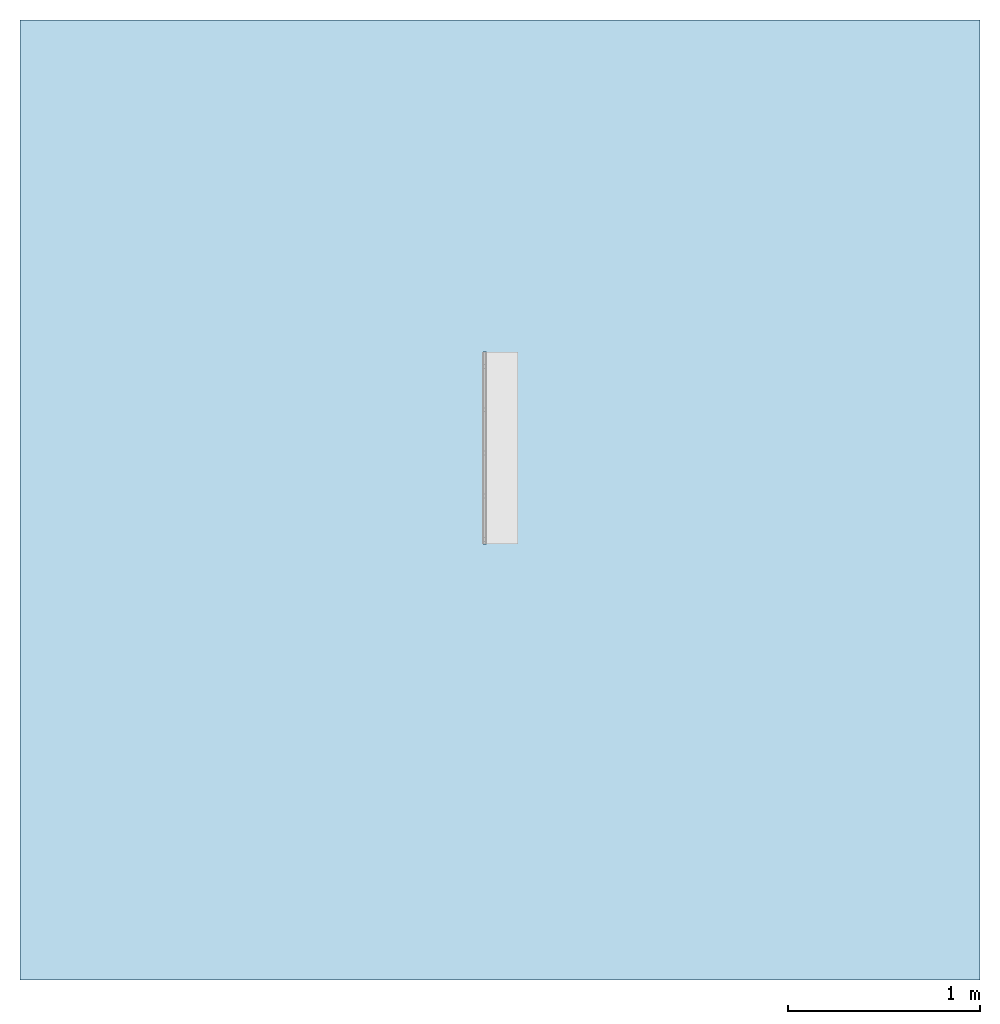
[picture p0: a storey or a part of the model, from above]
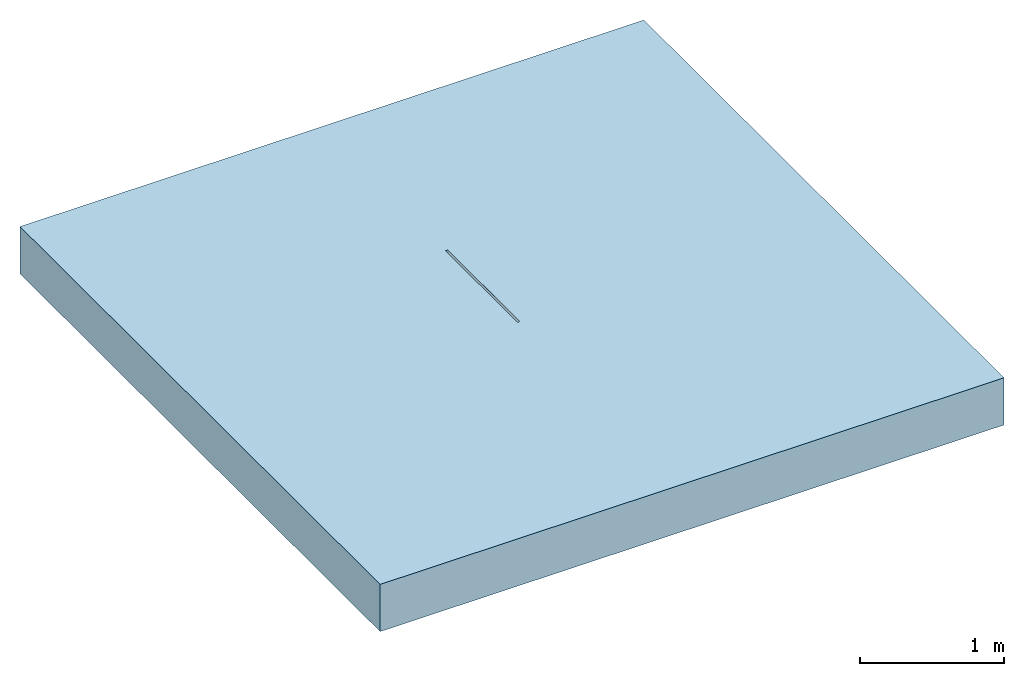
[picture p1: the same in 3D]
Properties of the parts of a building model (IFC2X3)

# File
Description: ViewDefinition [CoordinationView]
File name: 24151 - No 10.0 Constant Depth Channel - 1000mm LG - Invert Depth 235mm.ifc
Time: 2013-10-30T13:29:12
Written by: Autodesk Revit 2013
Made in: 20120221_2030(x64)

# IfcProject, Project Number
LongName: Project Name; Phase: Project Status

# IfcSite, Default
RefLatitude: 42, 21, 30, 344238; RefLongitude: -71, -3, -35, -194702; RefElevation: 0 mm

# IfcBuilding
Pset_BuildingCommon - NumberOfStoreys: 1
Other - Project Issue Date: Issue Date; Project Address: ## Street City, State Zip; Project Status: Project Status; Client Name: Owner; Project Number: Project Number; Project Name: Project Name

# IfcBuildingStorey, Level 1
LongName: Level 1; Elevation: 0 mm
Constraints - Elevation Base: 0; Elevation: 0 mm
Graphics - Line Pattern: Center; Symbol at End 2 Default: yes; Symbol: M_Level Head - Circle: M_Level Head - Circle; Symbol at End 1 Default: no; Color: 0; Line Weight: 1
Identity Data - Building Story: yes; Structural: no; Name: Level 1
Dimensions - Computation Height: 0 mm

# IfcBuildingElementProxy: 24151 - No 10.0 Constant Depth Channel - 1000mm LG - Invert Depth 235mm, Civil-Drainage-Channel-ACO-MultiDrain-M150DS-Brickslot-Channel-System:24151 - No 10.0 Constant Depth Channel - 1000mm LG - Invert Depth 235mm:24151 - No 10.0 Constant Depth Channel - 1000mm LG - Invert Depth 235mm:196059
In: Level 1
Material: Stainless Steel (F), Vienite® Synthetic Resin Concrete
Construction - 24187_Load Class C250 & D400_Brickslot_Access Unit_Stainless Steel_500mm Long: no; 23186_Load Class C250 & D400_Brickslot Grating_Stainless Steel_500mm Long: no; 23159_Universal Endcap (Male End): no; 23159_Universal Endcap (Female End): no; 23185_Load Class C250 & D400_Brickslot Grating_Stainless Steel_1000mm Long: yes; 24158_Sump Unit: no; Constant Depth Channel_500: no; 24157_Shallow Depth Channel with seal: no; 24156_Shallow Depth Channel: no; Constant Depth Channel_1000: yes
Dimensions - Brickslot Grating Void Depth: 0 mm; Brickslot Void Length: -1000 mm; FloorCut_Length: -1000 mm; Custom_Void_Length: 0 mm; Volume: 15462793 mm3; Brickslot Access Unit Void Bottom Depth: 5895 mm; Brickslot Access Unit Void Depth: 6000 mm; Length: 1000 mm; EndCap Position: 1000 mm; FloorCut_Width: 185 mm; GratingLength: 0 mm; EndCap_Height: -260 mm; Depth: 260 mm; Floor cut gap depth for access unit: 105 mm; InvDepth: 160 mm; Length Drain: -1000 mm; FloorCut_HorPosition: 92.5 mm; Floor Cut Gap: 105 mm; FloorCut_Depth: 260 mm
Phasing - Phase Created: New Construction
Constraints - Level: Level: Level 1; Moves With Nearby Elements: no
Pset_BuildingElementProxyCommon - Reference: 24151 - No 10.0 Constant Depth Channel - 1000mm LG - Invert Depth 235mm
Identity Data - Installation guidelines: http://www.aco.co.uk/download.php?id=173; Address: ACO Business Park, Hitchin Road, Shefford, Bedfordshire, United Kingdom SG17 5TE; Maintenance guidelines: http://www.aco.co.uk/download.php?id=173; Watermark 2: This file is water marked and users are prohibited to reproduce, adapt, distribute this information; Model Description: Channel drainage system; Price: POA - contact ACO; Watermarked By: www.aco.co.uk; e-mail Sales: customersupport@aco.co.uk; Fax: +44 (0)1462 815895; Product brochure: http://www.aco.co.uk/download.php?id=173; Watermarked With: BIM Manager Premium Suite; Telephone: +44 (0)1462 816666; Watermark 1: This file is the property of ACO Technologies PLC; Manufacturer: ACO Technologies plc - ACO Water Management Division; e-mail Technical: technical@aco.co.uk; OmniClass Number: 23.70.50.24; URL: www.aco.co.uk; Product Page URL: http://www.aco.co.uk/product_detail.php?id=58; Type Comments: ACO MultiDrain M150DS 10.0 Constant Depth Channel 1000mm Long; OmniClass Title: Rainwater Removal; Assembly Code: D2040; Cost: 0; Product Code: 24151; Assembly Description: Rain Water Drainage; Model: ACO MultiDrain MDS Brickslot - M150DS
Green Building Properties - Edge Rail Recyclable: Fully recyclable; Channel Recyclable: Fully recyclable; Channel Recycled Material Content: 20% minimum; Edge Rail Recycled Material Content: Between 40% - 90%
Materials and Finishes - Channel Colour: Brown; Edge Rail Material: Stainless Steel Grade 304; Channel Material: Vienite® Synthetic Resin Concrete; Edge Rail Colour: Self
Model Properties - End Cap Product code 23219: No. 306 Universal End Cap - 185mm wide x 310mm long - Spigot Ø110mm x 50mm long - Silver - Co-Polymer Polypropylene - 0.3kg; Brickslot Grating Product code 23185: Load Class C250/D400 - Brickslot Stainless Steel - 1000mm long x 105mm high - 10mm Slot - Intake area 10000mm²/m - 7.6kg; Brickslot Access Unit Product code 23187: Load Class C250/D400 - Brickslot Access Unit Stainless Steel - 500mm long x 105mm high - 10mm Slot - Intake area 10000mm²/m - 6.4kg; Brickslot Grating Product code 23186: Load Class C250/D400 -Brickslot Stainless Steel - 500mm long x 105mm high - 10mm Slot - Intake area 10000mm²/m - 3.8kg
Data - Installation - Concrete Grade: Refer to brochure; Product Weight: 26.7 Kg; Concrete Surround Volume - Load Class A 15 - Concrete Pavement: 0.10m³/m; Product Standard: BS EN 1433:2002, CE marked; Load Class: A 15 - D 400; ACO Hydraulic Design Software: http://www.acodesign.co.uk; Channel C.S.A: 0.026m²; Invert Depth: 235mm; Concrete Surround Volume - Load Class D 400 - Concrete Pavement: 0.23m³/m; Product Dimensions: 1000mm x 185mm x 260mm (LxWxH); Hydraulic Performance: http://www.aco.co.uk/download.php?id=173; Concrete Surround Volume - Load Class B 125 - C 250 - Concrete Pavement: 0.16m³/m; Pre-formed Outlet Ø: N/A
General - TagNumber: 0; SerialNumber: 0
Other - CreatedBy: www.aco.co.uk; Revision: 1

# IfcOpeningElement: Recess (2)
In: Level 1
Phasing - Phase Created: New Construction
Dimensions - Perimeter: 20000 mm; Thickness: 400 mm; Volume: 9950010000 mm3; Area: 25000000 mm2
Constraints - Level: Level: Level 1; Related to Mass: no; Room Bounding: yes; Height Offset From Level: 0 mm
Structural - Structural: no; Enable Analytical Model: no
Analytical Properties - Thermal Resistance (R): 0.477897; Thermal mass: 543920; Absorptance: 0.1; Roughness: 1; Heat Transfer Coefficient (U): 2.0925
Graphics - Coarse Scale Fill Color: 0
Construction - Default Thickness: 400 mm; Function: 0
Materials and Finishes - Structural Material: Earth

# IfcSlab: Floor:Generic Floor - 400mm, Floor:Generic Floor - 400mm:193825
In: Level 1
PredefinedType: FLOOR; Material: Earth 400 mm
Phasing - Phase Created: New Construction
Dimensions - Perimeter: 20000 mm; Thickness: 400 mm; Volume: 9950010000 mm3; Area: 25000000 mm2
Constraints - Level: Level: Level 1; Related to Mass: no; Room Bounding: yes; Height Offset From Level: 0 mm
Structural - Structural: no; Enable Analytical Model: no
Pset_SlabCommon - Reference: Generic Floor - 400mm; IsExternal: no; LoadBearing: yes
Analytical Properties - Thermal Resistance (R): 0.477897; Thermal mass: 543920; Absorptance: 0.1; Roughness: 1; Heat Transfer Coefficient (U): 2.0925
Graphics - Coarse Scale Fill Color: 0
Construction - Default Thickness: 400 mm; Function: 0
Materials and Finishes - Structural Material: Earth
